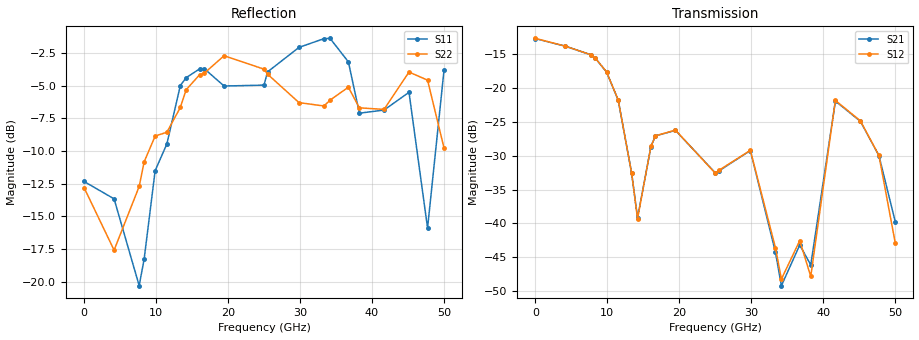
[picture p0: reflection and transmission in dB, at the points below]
!Keysight Technologies,N5245B,MY58422270,A.16.20.02
!Date: Thursday, March 05, 2026 00:57:14
!Correction: S11(C  2-Port  )
!S21(C  2-Port  )
!S12(C  2-Port  )
!S22(C  2-Port  )
!S2P File: Measurements: S11, S21, S12, S22:
# Hz S  dB  R 50
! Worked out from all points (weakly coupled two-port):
!   3201 points, 10 MHz to 50 GHz, reference 50 ohm
!   highest |S21| = -12.65 dB at 10 MHz (marker M1); lowest = -49.2 dB at 34.18 GHz (marker M2)
!   lowest |S11| = -20.3 dB at 7.665 GHz (marker M3), VSWR 1.21, Z = 41.3 - j1.13 ohm
!   |S11| at or under -10 dB: start of sweep to 10.37 GHz; 46.73 GHz to 48.26 GHz (1.53 GHz wide, 3.22 % of centre)
!   |S22| runs from -20.2 to -2.4 dB; largest |S21 - S12| = 0.0095
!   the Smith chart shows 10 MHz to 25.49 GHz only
!   S11 on the Smith chart (normalised r, x): 10 MHz: 1.64, -0.02; 9.883 GHz: 0.58, +0.03; 13.38 GHz: 0.81, +1.21; 16.05 GHz: 2.53, -2.26; 19.46 GHz: 0.41, -0.63; 25.49 GHz: 0.23, +0.10
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1e7  -12.34 -1.6  -12.65 3.1  -12.62 3.2  -12.81 32.4
4.181041e9  -13.67 -132.5  -13.79 -172.7  -13.78 -172.6  -17.60 -145.9
7.664719e9  -20.32 -171.9  -15.04 33.7  -15.03 33.7  -12.72 -139.7
8.352081e9  -18.29 -160.5  -15.58 1.9  -15.57 2.1  -10.84 -157.5
9.883025e9  -11.51 174.1  -17.60 -68.7  -17.58 -68.6  -8.86 151.4
1.15077e10  -9.47 119.1  -21.76 -142.1  -21.72 -142.1  -8.57 73.8
1.338232e10  -4.99 64.9  -32.62 153.6  -32.62 153.8  -6.67 -28.1
1.419466e10  -4.39 36.6  -39.20 -170.6  -39.31 -170.4  -5.31 -67.6
1.605367e10  -3.72 -23.3  -28.63 -177.9  -28.61 -177.7  -4.17 -128.4
1.667854e10  -3.69 -41.9  -27.06 159.9  -27.05 159.7  -4.06 -143.0
1.945923e10  -5.03 -109.0  -26.24 67.5  -26.20 67.3  -2.71 168.3
2.5005e10  -4.96 174.7  -32.54 -65.0  -32.60 -65.1  -3.74 70.2
2.548928e10  -3.95 167.5  -32.25 -71.2  -32.15 -70.7  -4.12 58.2
2.98634e10  -2.07 90.2  -29.22 155.6  -29.20 155.5  -6.30 -28.6
3.334708e10  -1.40 35.7  -44.27 -3.3  -43.61 -0.5  -6.56 -132.7
3.417504e10  -1.38 21.4  -49.23 -80.4  -48.25 -78.6  -6.11 -150.8
3.672141e10  -3.18 -31.9  -43.21 107.1  -42.57 104.2  -5.12 158.7
3.825235e10  -7.11 -21.8  -46.16 95.5  -47.85 -46.9  -6.70 132.3
4.167354e10  -6.87 -55.2  -21.91 -58.5  -21.81 -58.3  -6.82 112.3
4.51416e10  -5.51 -101.9  -24.89 88.8  -24.82 88.8  -3.96 74.6
4.771921e10  -15.91 69.2  -29.97 -16.3  -29.95 -16.9  -4.58 40.8
5e10  -3.84 -72.3  -39.80 -131.6  -42.97 -123.4  -9.76 7.9
